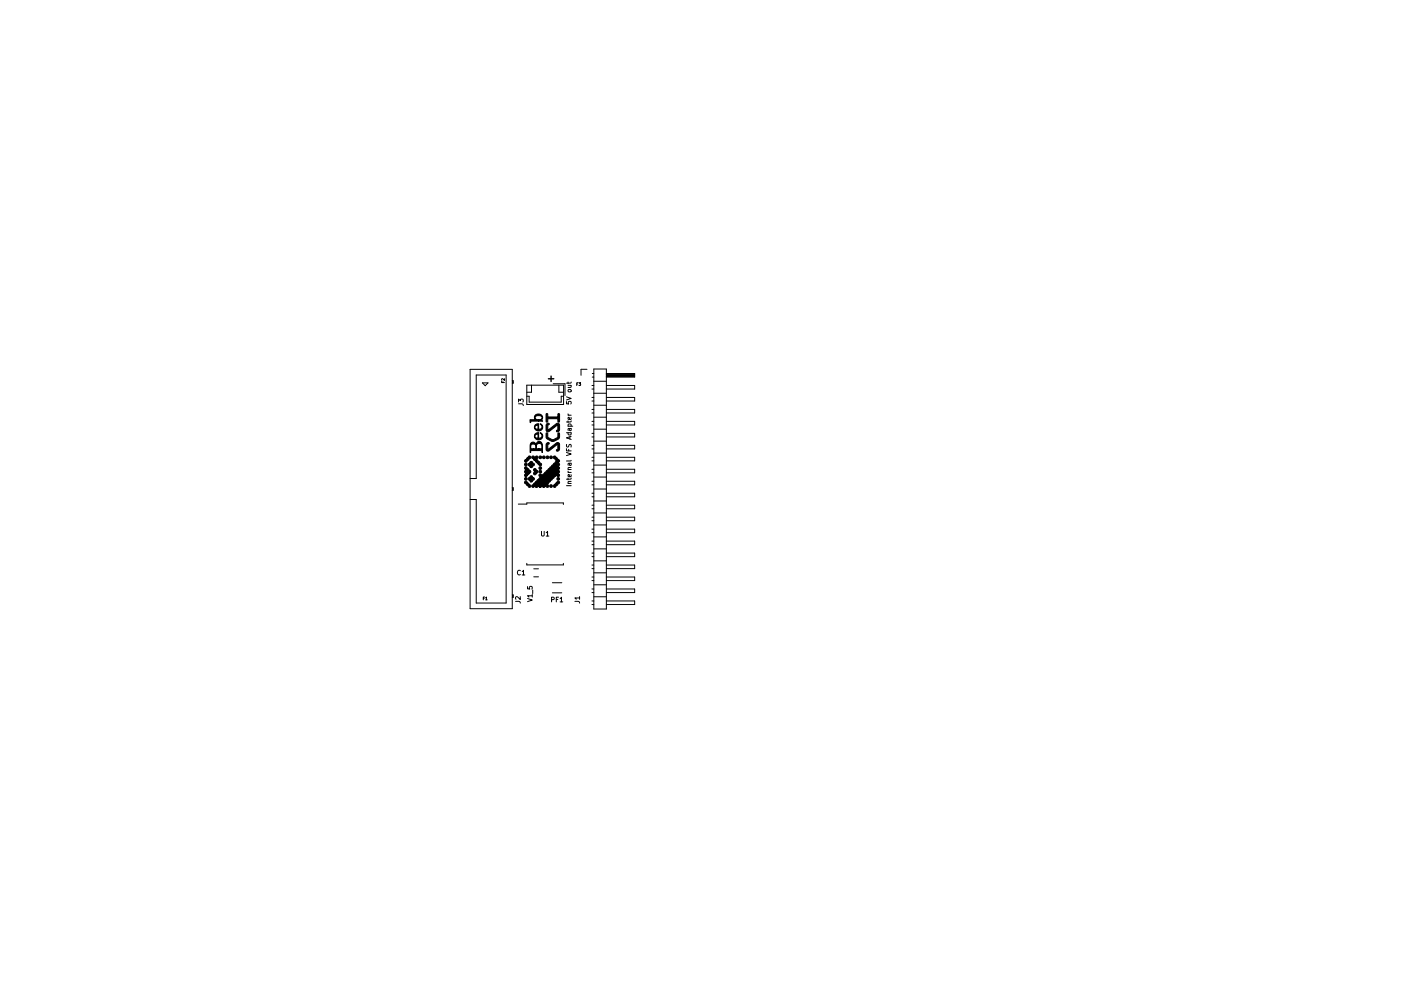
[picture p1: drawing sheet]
<svg xmlns="http://www.w3.org/2000/svg" width="297mm" height="210mm" viewBox="0 0 297 210" stroke-linecap="round" stroke-linejoin="round" font-family="sans-serif">
<g fill="none" stroke="#000" stroke-width=".21">
<path d="M99.7 78.4h8.9v50.7h-8.9zM124.5 78.4h-1.3v1.2M125.6 79.2h.3M125.9 78.3h2.7v50.9h-2.7zM128.6 79.2h6v.8h-6M128.6 79.3h6M128.6 79.4h6M128.6 79.5h6M128.6 79.7h6M128.6 79.8h6M128.6 79.9h6M102.3 81.2h1.2l-.6 .6z"/>
<path d="M106.4 80.9v.3h.6M106.6 81v.2M107 80.3v.4l-.5-.4-.1 .2v.2M108.6 80.8h.2v.5h-.2M108.7 80.8v.5M109.9 85.7h.9l.1 .4M109.9 85.3v-.6l.4 .3 .1-.3h.4v.6M111.7 81.7h7.8v4.1h-7.8zM111.7 84.1h.5v1.2h6.8v-1.2h.5M112.7 81.7v1.5h-1M117.3 81.4h2.5v2.5M118.5 81.7v1.5h1"/>
<path d="M120.1 96l1 .3-1 .4M120.1 95.2v.5h1M120.1 85.2v.5h.5l-.1-.5h.5v.5M120.1 84.2l1 .3-1 .4M120.1 91.8h1M120.1 94.3l.1 .5a.42 .42 0 0 0 .5-.5l.4 .1v.5M120.4 100l.2 .2M120.4 87.8l.2 .3M120.4 81.1v.3M120.4 89.3v.4M120.4 99.6h.7M120.4 90.4h1"/>
<path d="M120.4 88.1h.7M120.4 81.8h.7M120.5 91.8l-.1 .3 .2 .2 .5-.1v-.4M120.5 90.4l-.1-.3 .2-.1h.5v.4M120.5 82.7h.5l.1 .4h-.6zM120.6 95.3v.4M120.7 98.3l.2 .5 .2-.2v-.3M120.7 90.9l.2 .5 .2-.2v-.3M120.8 92.7v.4M121 81.8l.1 .3-.7 .1M121.1 88.6v.3l-.1 .1h-.5v-.4l.2-.1 .1 .5M121.1 99.2h-.6v.4"/>
<path d="M121.1 98.3h-.6v.4M121.1 97.7l-.1 .1h-.9M121.1 92.6l-1 .3 1 .3M121.1 90.9l-.6 .1v.3M121.1 89.3l-.1 .2h-.9M121.1 81.1l-.1 .2h-.9M122.3 81.5h.2M122.6 81.2h-.3v.6M122.7 81.2h.4l-.2 .2 .2 .1v.2h-.4M125.5 81.8h.4M125.5 82.5h.4M125.5 84.3h.4"/>
<path d="M125.5 85.1h.4M125.5 86.9h.4M125.5 87.6h.4M125.5 89.4h.4M125.5 90.2h.4M125.5 91.9h.4M125.5 92.7h.4M125.5 94.5h.4M125.5 95.2h.4M125.5 97h.4M125.5 97.8h.4M125.5 99.6h.4"/>
<path d="M125.6 80h.3M125.9 80.9h2.7M125.9 83.4h2.7M125.9 86h2.7M125.9 88.5h2.7M125.9 91.1h2.7M125.9 93.6h2.7M125.9 96.1h2.7M125.9 98.7h2.7M128.6 81.8h6v.7h-6M128.6 84.3h6v.8h-6M128.6 86.9h6v.7h-6"/>
<path d="M128.6 89.4h6v.8h-6M128.6 91.9h6v.8h-6M128.6 94.5h6v.7h-6M128.6 97h6v.8h-6M128.6 99.6h6v.7h-6M99.7 101.5h1.3v-21.9h6.3v48.3h-6.3v-21.9h-1.3M108.6 103.5h.2v.5h-.2M108.7 103.5v.5M109.9 107h1.8v-.3h7.7v.3M111.7 119.5v.4h7.7v-.4M114.8 112.7v.8l.2 .2 .4-.2v-.8M115.8 113l.3-.3v1"/>
<path d="M115.8 113.7h.6M120.1 103h1M120.4 102.6h.7M120.4 101.4v.4M120.4 100.2h.7M121.1 100.7v.3l-.1 .1h-.5v-.4h.2l.1 .4M121.1 102.1l-.6 .1v.4M121.1 101.4l-.1 .3h-.9M125.5 100.3h.4M125.5 102.1h.4M125.5 102.9h.4M125.5 104.6h.4"/>
<path d="M125.5 105.4h.4M125.5 107.2h.4M125.5 107.9h.4M125.5 109.7h.4M125.5 110.5h.4M125.5 112.3h.4M125.5 113h.4M125.5 114.8h.4M125.5 115.6h.4M125.5 117.3h.4M125.5 118.1h.4M125.5 119.9h.4"/>
<path d="M125.9 101.2h2.7M125.9 103.8h2.7M125.9 106.3h2.7M125.9 108.8h2.7M125.9 111.4h2.7M125.9 113.9h2.7M125.9 116.5h2.7M125.9 119h2.7M128.6 102.1h6v.8h-6M128.6 104.6h6v.8h-6M128.6 107.2h6v.7h-6M128.6 109.7h6v.8h-6"/>
<path d="M128.6 112.3h6v.7h-6M128.6 114.8h6v.8h-6M128.6 117.3h6v.8h-6M128.6 119.9h6v.7h-6M102.5 127h.2M102.8 126.7h-.3v.6M103 126.8l.1-.1v.6M103 127.3h.3M108.6 126.2h.2v.5h-.2M108.7 126.2v.5M109.3 127.6h.9l.1 .4M110.3 126.6v.6l-.7-.6-.3 .2 .1 .4"/>
<path d="M110.3 121.1a.44 .44 0 0 0-.6 .4 .44 .44 0 0 0 .6 .4M110.7 121.3l.3-.3v1M110.7 122h.6M111.8 127l1 .3-1 .3M111.8 124.5v.4l.5 .1v-.5h.5v.5M112.8 126.4h-1l.3 .3M112.8 126.1v.6M112.9 125.2v.7M113.2 122.4h1M113.2 120.7h1M116.9 127.2h.5l.1-.4-.6-.1v1M117.1 125.8h2"/>
<path d="M117.1 123.6h2M117.9 127.2h.4M118.4 126.7h-.5v1M118.8 127l.2-.3v1M118.8 127.7h.5M121.9 127.6h.8l.2 .4M122.9 126.9h-1l.3 .3M122.9 126.6v.6M125.5 120.6h.4M125.5 122.4h.4M125.5 123.2h.4M125.5 125h.4"/>
<path d="M125.5 125.7h.4M125.5 127.5h.4M125.5 128.3h.4M125.9 121.5h2.7M125.9 124.1h2.7M125.9 126.6h2.7M128.6 122.4h6v.8h-6M128.6 125h6v.7h-6M128.6 127.5h6v.8h-6"/>
</g>
<path d="M116.8 79.8v1.1M116.3 80.4h1.1" fill="none" stroke="#000" stroke-width=".3"/>
<g fill="#000" stroke="#000" stroke-width=".21">
<path d="M111.3 99.1h.4l.1 .3 .3 .1v.3h.3l.1 .2v.3h-.4v.3l-.3 .1v-.5h.2v-.2h-.2v.9l-.2 .2-.4-.2 .1-.3h.3v-.3l-.4-.2 .1-.3h.3v-.2l-.4-.2zM111.3 97.6l.3-.1 .1-.3 .3-.1 .1-.3 .4 .1v.3l-.4 .1v.3l-.3 .1-.2 .3h-.3zM112.1 98.3h.3v-.3l.3-.1 .2 .1v.3l.3 .1 .1 .2-.1 .2h-.3l-.1 .4h-.2l-.1-.5h.3v-.3h-.3v.8l-.1-.4-.4-.1zM112.4 89h1.2l-.3-.3 .1-.4 .2-.3 .4-.2 .8 .3 .2 .7a.33 .33 0 0 0 0 .6h-.8v-.3l.5-.1 .2-.3-.1-.3-.4-.2h-.6l-.3 .3 .1 .4 .6 .2v.3h-1.5l-.3 .3zM112.6 94l.6-.2 .4 .6 .4-.7 .7 .1 .3 .7v1.5h-.1l-.1-.4h-.5v-.4h.5l.1-.2-.1-.7-.5-.2-.4 .1-.2 .4v.6h.6v.4h-1.2v-.4h.5v-.6l-.3-.3-.5-.1-.2 .3-.1 .6 .6 .1v.4h-.5l-.1 .4h-.1v-1.5zM112.8 96.8h.3l.2 .3h.2l.1-.3h.4v.3l-.3 .2v.2l.3 .1v.3l.4 .1v.3l.4 .1-.1 .4h-.3l-.1-.4-.4-.1v-.2l-.3-.1-.1-.3-.3-.1-.1-.3-.3-.1zM113.2 99.5l.3-.1 .2 .4 .4 .2-.1 .3h-.3l-.2 .4-.4-.2 .1-.3h.3v-.2l-.4-.2zM113.5 92l.7-.2v1.2h.3l.4-.5-.1-.3-.3-.3 .1-.1 .4 .5v.6l-.4 .3-.5 .1v-1.1l-.4-.1-.2 .2-.1 .3 .2 .3 .5 .1v.3l-.4-.1-.4-.6zM113.5 90.1l.7-.2v1.2h.3l.4-.4-.1-.4-.3-.3 .1-.1 .4 .5v.6l-.4 .3-.5 .1v-1.1l-.4-.1-.2 .2-.1 .3 .2 .3 .5 .1v.3l-.4-.1-.4-.5zM115.9 94l.4-.1 .2 .1-.4 .4 .1 1 1.8-1.4 .4-.1 .2 .3v1.3l-.3 .2-.3-.1 .3-.3-.1-1-1.8 1.4h-.4l-.2-.3v-1.1zM115.9 89.9l.4-.1 .2 .1-.4 .4 .1 1 1.8-1.4 .4-.1 .2 .3v1.3l-.3 .2-.3-.1 .3-.3-.1-1-1.8 1.4h-.4l-.2-.3v-1.1zM115.8 91.9h.3l.1 .9 1 .5 1-.5 .1-.8 .2-.2 .1 1-.2 .3-.9 .5h-.6l-1.1-.7z"/>
<path d="M115.8 87.8l.3 .1v.6h2.2v-.6l.2-.1 .1 1.7h-.3v-.7h-2.2v.7l-.2 .1zM111.3 102.2l.3-.1 .2 .4 .3 .1v.3h.4v.4l-.4 .1-.1-.4-.4-.1v-.3h-.3zM112.1 101.4l.3-.1v-.3l.3-.1 .2 .2v.2l.3 .1 .1 .3-.1 .2h-.3l-.1 .3-.2 .1-.1-.6h.3v-.2h-.3v.7l-.1-.3-.4-.2zM117.4 96.8h.4l.1 .3 .2 .1 .1 .3 .4 .2-.1 .3-.3 .1v.2h.3l.1 .2-.1 .3h-.3v.3h.3l.1 .2-.1 .2-.3 .1v.2l.4 .2-.1 .3h-.3v.3l.4 .1v.3l-.4 .1-.1-.4h-.2v-.5h.2v-.2h-.2v-.6h.2v-.2h-.2v-.5h.2v-.3h-.2v2.5l-.4 .2v-.5h.2v-.3h-.2v-.5h.2v-.2h-.2v-.5h.2v-.3h-.2v2.5l-.4 .2v-.5h.2v-.3h-.2v-.5h.2v-.2h-.2v-.6h.2v-.2h-.2v2.5l-.4 .2v-.6h.3v-.2h-.3v-.5h.3v-.3h-.3v-.5h.3v-.2h-.3v2.4l-.1 .2h-.3v-.5h.3v-.2h-.3v-.5h.3v-.3h-.3v-.5h.3v-.2h-.3l.1 2.4-.3 .2h-.2v-.5h.3v-.2h-.3v-.6h.3v-.2h-.3v-.5h.3v-.3h-.3v2.6h.4v.4l-.3 .1-.2-.4h-.2v-.5h.2v-.3h-.2v-.5h.2v-.2h-.2v-.5h.2v-.3h-.2l-.1 2.6-.3 .1v-.5h.2v-.3h-.2v-.5h.2v-.2h-.2v-.6h.2v-.2h-.2v2.3l-.2-.4h-.2v-.5h.2v-.3h-.2v-.5h.2v-.2h-.2l-.1 1.9h-.3v-.5h.3v-.3h-.3v-.5h.3v-.2h-.3v1.5l-.1-.4h-.3v-.5h.3v-.3h-.3v1.2h-.3v-.5h.2v-.3h-.2v.8l-.2-.4h-.2l-.1 .4h-.4v-.5h.3l.1-.3 .3-.1 .1-.4h.3v-.3l.4-.1 .1-.3 .3-.1v-.2l-.4-.2v-.3h.4l.1 .4h.2l.1-.4h.3l.1-.3 .3-.1 .1-.4h.3v-.3l.4-.1v-.3h.4l.1-.4h.2v-.3l.4-.1 .1-.4h.3v-.2l-.4-.1v-.3l-.4-.1zM117.4 102.9h.3v-.3l.4-.1 .1-.4 .4 .1v.3l-.4 .1v.3l-.3 .1-.2 .4-.3-.1z"/>
<circle cx="111.5" cy="98.6" r=".29"/>
<circle cx="114.5" cy="99.3" r=".29"/>
<circle cx="114.5" cy="97" r=".29"/>
<circle cx="115.3" cy="97" r=".29"/>
<circle cx="116.1" cy="97" r=".29"/>
<circle cx="116.8" cy="97" r=".29"/>
<circle cx="111.5" cy="101.6" r=".29"/>
<circle cx="114.5" cy="100.1" r=".29"/>
<circle cx="116.8" cy="103.1" r=".29"/>
<circle cx="118.4" cy="101.6" r=".29"/>
</g>
</svg>
